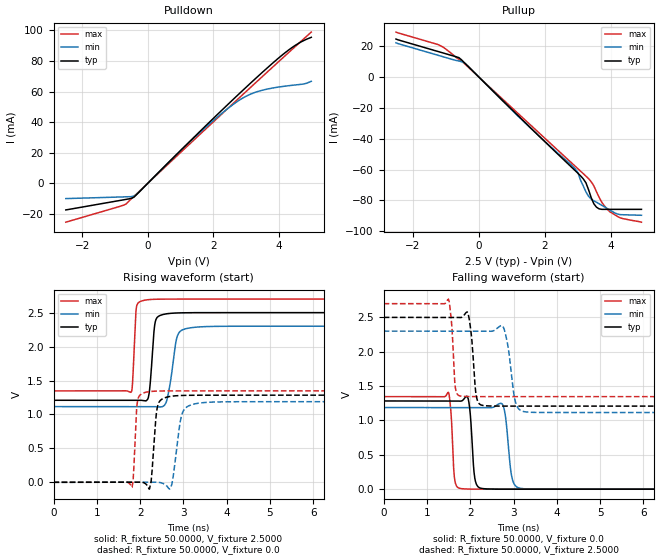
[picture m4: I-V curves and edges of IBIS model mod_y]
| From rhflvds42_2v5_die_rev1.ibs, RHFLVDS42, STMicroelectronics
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|   Model mod_y
[Model]   mod_y
Model_type 3-state
Polarity   Non-Inverting
Enable   Active-High
Vmeas  =   1.650V
Cref   =   10pF
C_comp   0.485pF   0.423pF   0.611pF
[Temperature Range]  25.0000   0.1250k   -55.0000
[Voltage Range]   2.5000V   2.3000V   2.7000V
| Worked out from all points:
|   slope of the pulldown table from 0 to 0.375 V, typ, clamps not added: 46.4 ohm
|   slope of the pullup table from 0 to 0.375 V, typ, clamps not added: 47.1 ohm
|   rising waveform, R_fixture 50.0000, V_fixture 2.5000: 20-80 % time 88.6ps typ, 160ps min, 55.8ps max; typ from 1.21 V to 2.5 V
|   rising waveform, R_fixture 50.0000, V_fixture 0.0: 20-80 % time 91.8ps typ, 150ps min, 59.8ps max; typ from 0 V to 1.28 V
|   falling waveform, R_fixture 50.0000, V_fixture 0.0: 20-80 % time 76.8ps typ, 109ps min, 61.4ps max; typ from 1.28 V to 0 V
|   falling waveform, R_fixture 50.0000, V_fixture 2.5000: 20-80 % time 91.1ps typ, 139ps min, 68.8ps max; typ from 2.5 V to 1.21 V
[Pulldown]
|Voltage   I(typ)   I(min)   I(max)
-2.5V     -17.32mA   -9.903mA   -25.33mA
-740mV    -10.72mA   -8.793mA   -14.23mA
-660mV    -10.42mA   -8.733mA   -13.45mA
-420mV    -9.012mA   -8.243mA   -8.471mA
-260mV    -5.615mA   -5.706mA   -5.245mA
1.58V     33.63mA    32.99mA    31.73mA
2.3V      48.55mA    46.42mA    46.07mA
2.78V     58.31mA    54.16mA    55.59mA
3.34V     69.44mA    59.94mA    66.64mA
4.22V     85.81mA    63.67mA    83.87mA
4.62V     91.71mA    64.64mA    91.63mA
5V        95.55mA    66.78mA    98.96mA
[Pullup]
|Voltage   I(typ)   I(min)   I(max)
-2.5V     24.51mA    22.06mA    29.02mA
-1.24V    16.51mA    14.06mA    21.02mA
-600mV    12.47mA    10.32mA    11.43mA
-440mV    9.364mA    9.156mA    8.786mA
2.84V     -59.17mA   -57.8mA    -56.37mA
3V        -62.43mA   -62.18mA   -59.53mA
3.08V     -64.13mA   -67.01mA   -61.1mA
3.32V     -73.06mA   -77.34mA   -65.92mA
3.56V     -84.4mA    -81.2mA    -74.39mA
3.96V     -85.8mA    -86.2mA    -87.33mA
4.28V     -85.8mA    -89.25mA   -91.34mA
4.92V     -85.8mA    -89.65mA   -94.13mA
|[GND_clamp]
||Voltage   I(typ)   I(min)   I(max)
|  -2.50   -46.3930MA   -31.4440MA   -67.7400MA
|  -2.44   -44.0060MA   -29.6570MA   -64.4780MA
|  -2.38   -41.6200MA   -27.8700MA   -61.2170MA
|  -2.32   -39.2340MA   -26.0830MA   -57.9550MA
|  -2.26   -36.8470MA   -24.2960MA   -54.6940MA
|  -2.20   -34.4610MA   -22.5090MA   -51.4320MA
|  -2.14   -32.0740MA   -20.7220MA   -48.1710MA
|  -2.08   -29.6880MA   -18.9350MA   -44.9090MA
|  -2.02   -27.3020MA   -17.1480MA   -41.6480MA
|  -1.96   -24.9150MA   -15.3610MA   -38.3860MA
|  -1.90   -22.5290MA   -13.5730MA   -35.1240MA
|  -1.84   -20.1420MA   -11.7860MA   -31.8630MA
|  -1.78   -17.7560MA   -9.9994MA   -28.6010MA
|  -1.72   -15.3700MA   -8.2124MA   -25.3400MA
|  -1.66   -12.9830MA   -6.4253MA   -22.0780MA
|  -1.60   -10.5970MA   -4.6383MA   -18.8170MA
|  -1.54   -8.2103MA   -2.8619MA   -15.5550MA
|  -1.48   -5.8239MA   -1.6562MA   -12.2940MA
|  -1.42   -3.4375MA   -0.7310MA   -9.0320MA
|  -1.36   -1.5577MA   -0.1317MA   -5.7704MA
|  -1.30   -0.3487MA   -21.6830kA   -2.5091MA
|  -1.24   -31.3430kA   -3.5713kA   -0.4597MA
|  -1.18   -2.8176kA   -0.5882kA   -17.0420kA
|  -1.12   -0.2534kA   -96.9240A   -0.6322kA
|  -1.06   -22.8110A   -15.9920A   -23.4910A
|  -1.00   -2.0775A   -2.6585A   -0.8991A
|  -0.94   -0.2102A   -0.4598A   -57.2200mA
|  -0.88   -39.6750mA   -95.3920mA   -22.9680mA
|  -0.82   -21.9270mA   -33.2550mA   -18.9940mA
|  -0.76   -18.1300mA   -21.0230mA   -16.5710mA
|  -0.70   -15.8920mA   -17.1560mA   -14.6310mA
|  -0.64   -14.1310mA   -14.8620mA   -13.0610mA
|  -0.58   -12.6290mA   -13.0660mA   -11.7300mA
|  -0.52   -11.2580mA   -11.5420mA   -10.4920mA
|  -0.46   -9.9400mA   -10.1440mA   -9.2778mA
|  -0.40   -8.6389mA   -8.7966mA   -8.0675mA
|  -0.34   -7.3423mA   -7.4677mA   -6.8577mA
|  -0.28   -6.0465mA   -6.1456mA   -5.6479mA
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[Ramp]
| variable   typ   min   max
dV/dt_r   0.7702/0.1134n   0.7126/0.1704n   0.8083/0.1203n
dV/dt_f   0.7746/0.1273n   0.7105/0.1632n   0.8119/0.1176n
R_load = 50.0000
[Rising Waveform]
R_fixture= 50.0000
V_fixture= 2.5000
V_fixture_min= 2.3000
V_fixture_max= 2.7000
|time   V(typ)   V(min)   V(max)
0s        1.209V     1.116V     1.347V
1.792ns   1.209V     1.116V     1.327V
1.912ns   1.209V     1.116V     2.562V
2.064ns   1.205V     1.116V     2.677V
2.208ns   1.306V     1.116V     2.692V
2.352ns   2.367V     1.114V     2.697V
2.504ns   2.468V     1.113V     2.699V
2.856ns   2.495V     2.145V     2.7V
3.024ns   2.498V     2.257V     2.7V
8ns       2.5V       2.3V       2.7V
[Rising Waveform]
R_fixture= 50.0000
V_fixture= 0.0
V_fixture_min= 0.0
V_fixture_max= 0.0
|time   V(typ)   V(min)   V(max)
0s        8.255nV    3.07uV     631.7pV
1.816ns   -26.04uV   8.455uV    -74.18mV
1.928ns   234.5uV    -13.79uV   1.141V
2.128ns   -22.12mV   -72.74uV   1.326V
2.256ns   17.35mV    591.3uV    1.339V
2.4ns     1.113V     1.141mV    1.344V
2.592ns   1.25V      -40.31mV   1.346V
2.96ns    1.279V     988.3mV    1.347V
3.184ns   1.282V     1.142V     1.347V
8ns       1.284V     1.188V     1.347V
[Falling Waveform]
R_fixture= 50.0000
V_fixture= 0.0
V_fixture_min= 0.0
V_fixture_max= 0.0
|time   V(typ)   V(min)   V(max)
0s        1.284V     1.188V     1.347V
1.504ns   1.284V     1.188V     1.398V
1.632ns   1.284V     1.188V     178.5mV
1.752ns   1.281V     1.188V     13.2mV
1.952ns   1.319V     1.188V     1.64mV
2.096ns   197.9mV    1.188V     436.6uV
2.232ns   15.63mV    1.188V     135.7uV
2.744ns   154.5uV    1.235V     2.151uV
3.112ns   7.561uV    20.14mV    -34.18nV
8ns       -324.4nV   3.046uV    -181.5nV
[Falling Waveform]
R_fixture= 50.0000
V_fixture= 2.5000
V_fixture_min= 2.3000
V_fixture_max= 2.7000
|time   V(typ)   V(min)   V(max)
0s        2.5V       2.3V       2.7V
1.496ns   2.5V       2.3V       2.767V
1.648ns   2.5V       2.3V       1.514V
1.744ns   2.498V     2.3V       1.36V
1.952ns   2.551V     2.3V       1.348V
2.128ns   1.402V     2.3V       1.347V
2.256ns   1.224V     2.3V       1.347V
2.768ns   1.209V     2.353V     1.347V
3.216ns   1.209V     1.132V     1.347V
8ns       1.209V     1.116V     1.347V
